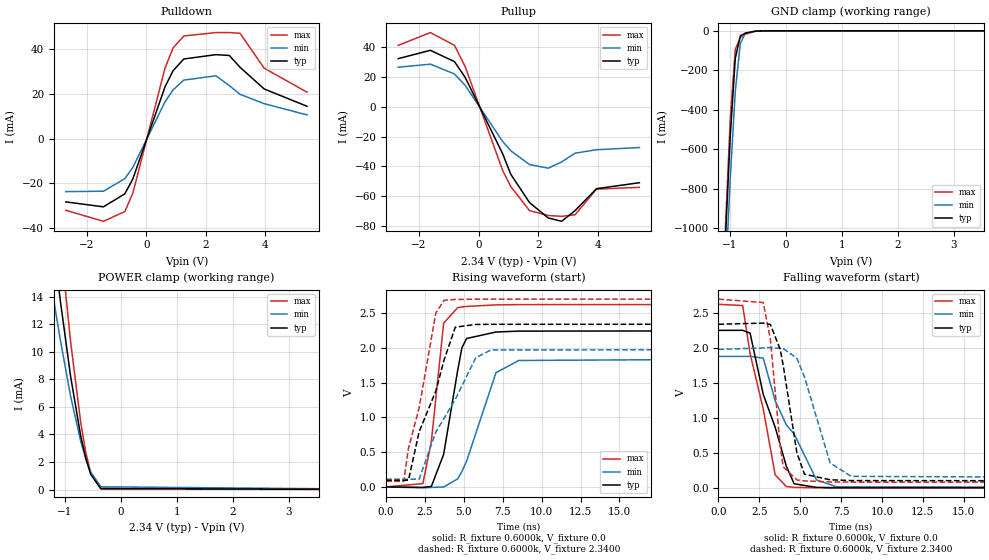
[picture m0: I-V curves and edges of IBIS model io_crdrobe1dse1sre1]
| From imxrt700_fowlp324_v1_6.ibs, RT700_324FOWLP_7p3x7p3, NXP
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[Model] io_crdrobe1dse1sre1
|   Model io_crdrobe1dse1sre1
| This model was characterised for following simulation conditions:
| External (pad) voltage:
|   - Typ: 2.34V,   - Min: 1.98V,   - Max: 2.7V
| Library cells for typ/min/max conditions are connected as defined below:
|  PAD_IO - External Pad
|  ipp_do - Core Input
|  ipp_obe - Output Buffer Enable
|  ASRCN3V3[3] - NC
|  ASRCN3V3[4] - NC
|  ASRCP3V3[4] - NC
|  REFAPBIAS3V3 - gnde
|  REFBAMPL3V3 - vdd1v8
|  REFCAMPH3V3 - vdd1v8
|  REFDNBIAS3V3 - vdd1v8
|  REFH3V3 - REFH3V3
|  REFL3V3 - REFL3V3
|  gnde - gnde
|  ipp_dse - vdd
|  ipp_ina235_3v - NC
|  ipp_ina40_3v - NC
|  ipp_ina_mux - NC
|  ipp_ind - NC
|  ipp_ind_1p8v - NC
|  ipp_ind_3v - NC
|  ipp_sre - vdd
|  vdd - vdd
|  vdd1v8 - vdd1v8
|  vdda - vdde3v3
|  vdde3v3 - vdde3v3
| All other pins connected to ground
Model_type I/O
Polarity   Non-Inverting
Enable   Active-High
Vinl =   0.7020V
Vinh =   1.6300V
Vmeas =  1.1700V
Cref =   15.0000pF
Rref =   0.6000k
Vref =   0.0V
C_comp   3.9951pF   3.8194pF   4.1033pF
|C_comp_pullup   0.5141pF   0.5881pF   0.4996pF
|C_comp_pulldown   2.0716pF   2.1607pF   1.8543pF
[Model Spec]
| variable   typ   min   max
Vinh   1.6300V   NA   NA
Vinl   0.7020V   NA   NA
Vref   0.0V   0.0V   0.0V
Cref   15.0000pF   15.0000pF   15.0000pF
Rref   0.6000k   0.6000k   0.6000k
[Receiver Thresholds]
Vcross_high  =   0.0V
Vcross_low  =   0.0V
Vdiff_ac  =   0.0V
Vdiff_dc  =   0.0V
Tdiffslew_ac  =   0.0S
[Temperature Range]   25.0000   0.1250k   -40.0000
[Voltage Range]   2.3400V   1.9800V   2.7000V
[Pullup Reference]   2.3400V   1.9800V   2.7000V
[Pulldown Reference]   0.0V   0.0V   0.0V
[POWER Clamp Reference]   2.3400V   1.9800V   2.7000V
[GND Clamp Reference]   0.0V   0.0V   0.0V
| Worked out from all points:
|   slope of the pulldown table from 0 to 0.351 V, typ, clamps not added: 25.9 ohm
|   slope of the pullup table from 0 to 0.351 V, typ, clamps not added: 23.9 ohm
|   GND clamp passes 1 mA (typ) near -0.49 V on its own axis
|   POWER clamp passes 1 mA (typ) near -0.53 V on its own axis
|   rising waveform, R_fixture 0.6000k, V_fixture 0.0: 20-80 % time 1.01ns typ, 1.62ns min, 726ps max; typ from 0 V to 2.25 V
|   rising waveform, R_fixture 0.6000k, V_fixture 2.3400: 20-80 % time 1.99ns typ, 2.68ns min, 1.48ns max; typ from 0.094 V to 2.34 V
|   falling waveform, R_fixture 0.6000k, V_fixture 0.0: 20-80 % time 1.77ns typ, 2.34ns min, 1.42ns max; typ from 2.25 V to 0 V
|   falling waveform, R_fixture 0.6000k, V_fixture 2.3400: 20-80 % time 898ps typ, 1.4ns min, 627ps max; typ from 2.34 V to 0.094 V
[Pulldown]
|Voltage   I(typ)   I(min)   I(max)
-2.7V     -28.24mA   -23.65mA   -31.99mA
-1.44V    -30.44mA   -23.46mA   -36.9mA
-720mV    -24.64mA   -17.86mA   -32.55mA
-450mV    -17.94mA   -12.78mA   -24.31mA
630mV     23.17mA    16.47mA    31.53mA
900mV     30.36mA    21.79mA    40.52mA
1.26V     35.6mA     26.18mA    45.89mA
2.34V     37.55mA    28.09mA    47.4mA
2.79V     37.18mA    23.71mA    47.41mA
3.15V     31.9mA     19.83mA    47.08mA
3.96V     22.22mA    15.65mA    31.51mA
5.4V      14.48mA    10.63mA    20.78mA
[Pullup]
|Voltage   I(typ)   I(min)   I(max)
-2.7V     32.17mA    26.42mA    41.07mA
-1.62V    37.75mA    28.48mA    49.64mA
-810mV    30.19mA    21.88mA    41.07mA
-450mV    19.57mA    14.2mA     26.75mA
810mV     -31.62mA   -23.37mA   -42.81mA
1.08V     -45.27mA   -29.51mA   -53.51mA
1.71V     -64.26mA   -38.77mA   -69.65mA
2.34V     -74.59mA   -41.23mA   -72.91mA
2.79V     -76.8mA    -37.01mA   -73.48mA
3.24V     -69.65mA   -31.16mA   -72.4mA
3.96V     -54.95mA   -28.85mA   -55.25mA
5.4V      -50.96mA   -27.4mA    -54.05mA
[GND_clamp]
|Voltage   I(typ)   I(min)   I(max)
-2.7V     -12.91A    -12.88A    -13.56A
-1.08V    -1.077A    -1.286A    -1.025A
-990mV    -533.6mA   -749.4mA   -449.1mA
-900mV    -139.2mA   -307mA     -94.25mA
-810mV    -25.49mA   -63.91mA   -32.87mA
-720mV    -11.78mA   -11.41mA   -16.65mA
-540mV    -1.684mA   -1.901mA   -2.149mA
-360mV    -36.04uA   -133.3uA   -15.05uA
5.4V      0A         0A         0A
[POWER_clamp]
|Voltage   I(typ)   I(min)   I(max)
-2.7V     73.96mA    57.58mA    95.4mA
-1.44V    26.15mA    20.18mA    34.67mA
-1.35V    22.86mA    17.7mA     30.34mA
-1.26V    19.66mA    15.3mA     26.09mA
-1.17V    16.56mA    12.98mA    21.97mA
-1.08V    13.59mA    10.78mA    17.99mA
-900mV    8.212mA    6.776mA    10.73mA
-720mV    3.9mA      3.518mA    4.888mA
-630mV    2.284mA    2.252mA    2.724mA
-540mV    1.103mA    1.268mA    1.195mA
-360mV    77.93uA    204.3uA    41.52uA
5.4V      0A         0A         0A
[Ramp]
| variable   typ   min   max
dV/dt_r  1.3518/1.0069n   1.1288/1.6186n   1.5755/0.7263n
dV/dt_f  1.3475/0.8978n   1.1218/1.3992n   1.5719/0.6275n
R_load = 0.6000k
[Rising Waveform]
R_fixture= 0.6000k
V_fixture= 0.0
V_fixture_min= 0.0
V_fixture_max= 0.0
|time   V(typ)   V(min)   V(max)
0s        54.47nV    1.425uV    18.12nV
2.36ns    -6.455mV   -13.67mV   47.62mV
2.905ns   6.495mV    -7.219mV   652.5mV
3.695ns   467.5mV    -1.992mV   2.353V
4.592ns   1.667V     115mV      2.577V
4.869ns   2.001V     220.2mV    2.587V
5.174ns   2.134V     372.9mV    2.595V
7.058ns   2.227V     1.643V     2.617V
8.526ns   2.24V      1.818V     2.621V
60ns      2.253V     1.881V     2.626V
[Rising Waveform]
R_fixture= 0.6000k
V_fixture= 2.3400
V_fixture_min= 1.9800
V_fixture_max= 2.7000
|time   V(typ)   V(min)   V(max)
0s        94.13mV    110.3mV    80.1mV
1.134ns   93.57mV    110.2mV    79.77mV
1.435ns   97.56mV    109.9mV    557mV
2.118ns   791.6mV    110mV      1.134V
3.196ns   1.38V      790.7mV    2.503V
3.725ns   1.827V     987.9mV    2.683V
4.446ns   2.297V     1.259V     2.695V
5.758ns   2.336V     1.857V     2.699V
6.733ns   2.338V     1.969V     2.699V
60ns      2.34V      1.98V      2.7V
[Falling Waveform]
R_fixture= 0.6000k
V_fixture= 0.0
V_fixture_min= 0.0
V_fixture_max= 0.0
|time   V(typ)   V(min)   V(max)
0s        2.253V     1.881V     2.626V
1.48ns    2.254V     1.881V     2.608V
1.933ns   2.213V     1.881V     1.92V
2.736ns   1.338V     1.856V     1.128V
3.47ns    865.7mV    1.245V     184.5mV
4.15ns    308.2mV    900.4mV    18.52mV
4.628ns   58.52mV    770.6mV    7.186mV
5.996ns   6.508mV    113.4mV    1.114mV
7.243ns   2.463mV    14.12mV    307.8uV
60ns      2.612uV    7.08uV     475.4nV
[Falling Waveform]
R_fixture= 0.6000k
V_fixture= 2.3400
V_fixture_min= 1.9800
V_fixture_max= 2.7000
|time   V(typ)   V(min)   V(max)
0s        2.34V      1.98V      2.7V
2.739ns   2.357V     2.002V     2.651V
3.174ns   2.337V     2.009V     2.122V
3.776ns   1.979V     1.995V     593.6mV
3.959ns   1.753V     1.992V     300.8mV
4.792ns   502.8mV    1.855V     113.5mV
5.257ns   195.7mV    1.588V     99.27mV
6.825ns   115.5mV    356.6mV    84.97mV
8.111ns   104.2mV    164.8mV    82.12mV
60ns      94.14mV    110.3mV    80.1mV
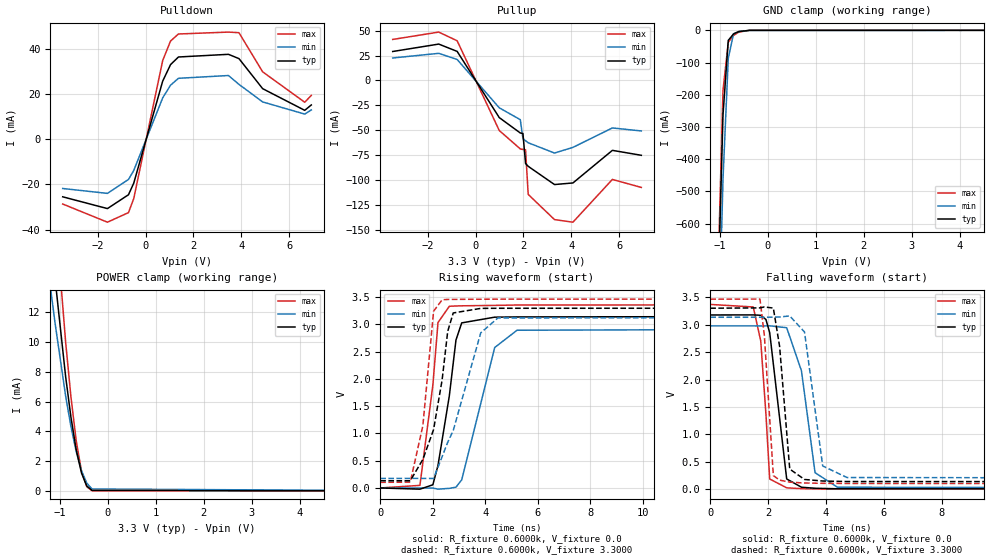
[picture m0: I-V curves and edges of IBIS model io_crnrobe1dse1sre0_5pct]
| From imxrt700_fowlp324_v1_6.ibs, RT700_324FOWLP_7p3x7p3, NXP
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[Model] io_crnrobe1dse1sre0_5pct
|   Model io_crnrobe1dse1sre0_5pct
| This model was characterised for following simulation conditions:
| External (pad) voltage:
|   - Typ: 3.3V,   - Min: 3.135V,   - Max: 3.465V
| Library cells for typ/min/max conditions are connected as defined below:
|  PAD_IO - External Pad
|  ipp_do - Core Input
|  ipp_obe - Output Buffer Enable
|  ASRCN3V3[3] - NC
|  ASRCN3V3[4] - NC
|  ASRCP3V3[4] - NC
|  REFAPBIAS3V3 - gnde
|  REFBAMPL3V3 - vdd1v8
|  REFCAMPH3V3 - vdd1v8
|  REFDNBIAS3V3 - vdd1v8
|  REFH3V3 - REFH3V3
|  REFL3V3 - REFL3V3
|  gnde - gnde
|  ipp_dse - vdd
|  ipp_ina235_3v - NC
|  ipp_ina40_3v - NC
|  ipp_ina_mux - NC
|  ipp_ind - NC
|  ipp_ind_1p8v - NC
|  ipp_ind_3v - NC
|  ipp_sre - gnde
|  vdd - vdd
|  vdd1v8 - vdd1v8
|  vdda - vdde3v3
|  vdde3v3 - vdde3v3
| All other pins connected to ground
Model_type I/O
Polarity   Non-Inverting
Enable   Active-High
Vinl =   0.9900V
Vinh =   2.3100V
Vmeas =  1.6500V
Cref =   15.0000pF
Rref =   0.6000k
Vref =   0.0V
C_comp   4.0038pF   3.8208pF   4.1241pF
|C_comp_pullup   0.5150pF   0.5903pF   0.4959pF
|C_comp_pulldown   2.0815pF   2.1810pF   1.8613pF
[Model Spec]
| variable   typ   min   max
Vinh   2.3100V   NA   NA
Vinl   0.9900V   NA   NA
Vref   0.0V   0.0V   0.0V
Cref   15.0000pF   15.0000pF   15.0000pF
Rref   0.6000k   0.6000k   0.6000k
[Receiver Thresholds]
Vcross_high  =   0.0V
Vcross_low  =   0.0V
Vdiff_ac  =   0.0V
Vdiff_dc  =   0.0V
Tdiffslew_ac  =   0.0S
[Temperature Range]   25.0000   0.1250k   -40.0000
[Voltage Range]   3.3000V   3.1350V   3.4650V
[Pullup Reference]   3.3000V   3.1350V   3.4650V
[Pulldown Reference]   0.0V   0.0V   0.0V
[POWER Clamp Reference]   3.3000V   3.1350V   3.4650V
[GND Clamp Reference]   0.0V   0.0V   0.0V
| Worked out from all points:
|   slope of the pulldown table from 0 to 0.495 V, typ, clamps not added: 26.4 ohm
|   slope of the pullup table from 0 to 0.495 V, typ, clamps not added: 24.4 ohm
|   GND clamp passes 1 mA (typ) near -0.50 V on its own axis
|   POWER clamp passes 1 mA (typ) near -0.52 V on its own axis
|   rising waveform, R_fixture 0.6000k, V_fixture 0.0: 20-80 % time 549ps typ, 813ps min, 418ps max; typ from 0 V to 3.18 V
|   rising waveform, R_fixture 0.6000k, V_fixture 3.3000: 20-80 % time 718ps typ, 1.14ns min, 459ps max; typ from 0.133 V to 3.3 V
|   falling waveform, R_fixture 0.6000k, V_fixture 0.0: 20-80 % time 329ps typ, 474ps min, 238ps max; typ from 3.18 V to 0 V
|   falling waveform, R_fixture 0.6000k, V_fixture 3.3000: 20-80 % time 280ps typ, 398ps min, 209ps max; typ from 3.3 V to 0.133 V
[Pulldown]
|Voltage   I(typ)   I(min)   I(max)
-3.465V   -25.47mA   -21.79mA   -28.66mA
-1.595V   -30.68mA   -23.95mA   -36.7mA
-715mV    -24.55mA   -17.79mA   -32.46mA
-495mV    -19.43mA   -13.83mA   -26.26mA
715mV     25.71mA    18.31mA    34.82mA
1.045V    33.06mA    23.94mA    43.49mA
1.375V    36.41mA    26.98mA    46.59mA
3.465V    37.59mA    28.21mA    47.43mA
3.905V    35.69mA    24.29mA    47.16mA
4.895V    22.39mA    16.52mA    29.84mA
6.655V    12.8mA     11.14mA    16.38mA
6.93V     15.19mA    12.98mA    19.44mA
[Pullup]
|Voltage   I(typ)   I(min)   I(max)
-3.465V   29.1mA     22.59mA    41.21mA
-1.54V    36.55mA    27.24mA    48.59mA
-770mV    29.19mA    21.06mA    39.85mA
990mV     -37.26mA   -27.44mA   -50.23mA
1.87V     -52.73mA   -39.38mA   -68.73mA
1.98V     -53.28mA   -58.42mA   -69.28mA
2.09V     -83.35mA   -60.56mA   -69.66mA
2.2V      -86.2mA    -62.53mA   -114.4mA
3.3V      -104.5mA   -72.86mA   -139.7mA
4.07V     -102.9mA   -67.18mA   -142.3mA
5.72V     -70.17mA   -47.67mA   -99.37mA
6.93V     -75.13mA   -50.69mA   -107.4mA
[GND_clamp]
|Voltage   I(typ)   I(min)   I(max)
-3.465V   -18.65A    -18.54A    -19.59A
-1.045V   -856.3mA   -1.07A     -789.2mA
-935mV    -262.9mA   -462.2mA   -186.4mA
-825mV    -31.14mA   -87.01mA   -37.16mA
-715mV    -11.21mA   -10.51mA   -15.88mA
-605mV    -3.859mA   -3.519mA   -5.394mA
-385mV    -79.67uA   -219.6uA   -43.93uA
6.93V     0A         0A         0A
[POWER_clamp]
|Voltage   I(typ)   I(min)   I(max)
-3.465V   98.91mA    78.43mA    126mA
-1.43V    25.78mA    19.9mA     34.19mA
-1.32V    21.78mA    16.89mA    28.92mA
-1.21V    17.92mA    14mA       23.79mA
-1.1V     14.24mA    11.26mA    18.86mA
-880mV    7.673mA    6.373mA    9.998mA
-770mV    4.965mA    4.333mA    6.33mA
-660mV    2.777mA    2.644mA    3.379mA
-550mV    1.212mA    1.363mA    1.332mA
-440mV    333.5uA    531.5uA    282.6uA
-330mV    37.61uA    130.9uA    15.04uA
6.93V     0A         0A         0A
[Ramp]
| variable   typ   min   max
dV/dt_r  1.9062/0.5490n   1.7865/0.8131n   2.0217/0.4182n
dV/dt_f  1.9001/0.2799n   1.7755/0.3982n   2.0172/0.2091n
R_load = 0.6000k
[Rising Waveform]
R_fixture= 0.6000k
V_fixture= 0.0
V_fixture_min= 0.0
V_fixture_max= 0.0
|time   V(typ)   V(min)   V(max)
0s        57.42nV    1.437uV    26.77nV
1.51ns    -22.02mV   -541.7uV   47.52mV
2.002ns   58.42mV    -1.774mV   1.884V
2.198ns   414mV      -21.5mV    3.034V
2.63ns    1.691V     -7.389mV   3.333V
2.882ns   2.712V     14.49mV    3.338V
3.101ns   3.028V     148.3mV    3.341V
4.357ns   3.133V     2.576V     3.349V
5.207ns   3.137V     2.893V     3.356V
60ns      3.177V     2.978V     3.369V
[Rising Waveform]
R_fixture= 0.6000k
V_fixture= 3.3000
V_fixture_min= 3.1350
V_fixture_max= 3.4650
|time   V(typ)   V(min)   V(max)
0s        133.2mV    175.8mV    103mV
1.142ns   132.4mV    175.8mV    107.2mV
1.622ns   523.3mV    175.6mV    1.143V
2.03ns    1.071V     174.4mV    3.242V
2.355ns   1.982V     574.3mV    3.452V
2.568ns   2.873V     837.9mV    3.458V
2.778ns   3.21V      1.053V     3.459V
3.826ns   3.294V     2.845V     3.462V
4.479ns   3.296V     3.119V     3.463V
60ns      3.3V       3.135V     3.465V
[Falling Waveform]
R_fixture= 0.6000k
V_fixture= 0.0
V_fixture_min= 0.0
V_fixture_max= 0.0
|time   V(typ)   V(min)   V(max)
0s        3.177V     2.978V     3.369V
1.485ns   3.178V     2.978V     3.323V
1.744ns   3.171V     2.977V     2.7V
1.923ns   3.094V     2.978V     1.366V
2.053ns   2.854V     2.979V     185.4mV
2.64ns    186.1mV    2.944V     24.21mV
3.15ns    35.73mV    2.159V     9.592mV
3.62ns    16.72mV    300.3mV    4.641mV
4.397ns   7.244mV    34.55mV    1.722mV
60ns      1.139uV    1.872uV    979nV
[Falling Waveform]
R_fixture= 0.6000k
V_fixture= 3.3000
V_fixture_min= 3.1350
V_fixture_max= 3.4650
|time   V(typ)   V(min)   V(max)
0s        3.3V       3.135V     3.465V
1.717ns   3.306V     3.135V     3.467V
1.868ns   3.323V     3.134V     2.804V
2.179ns   3.303V     3.138V     247.4mV
2.395ns   2.605V     3.14V      165.1mV
2.745ns   366.4mV    3.159V     128mV
3.256ns   176.7mV    2.866V     112.4mV
3.884ns   148.6mV    423.4mV    106.5mV
4.724ns   139.3mV    212.2mV    104.2mV
60ns      133.2mV    175.8mV    103mV
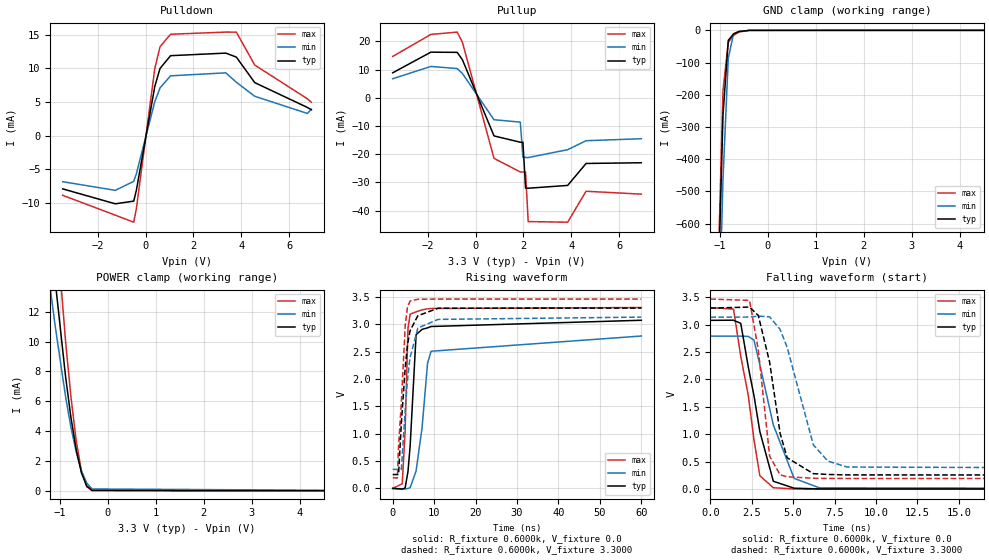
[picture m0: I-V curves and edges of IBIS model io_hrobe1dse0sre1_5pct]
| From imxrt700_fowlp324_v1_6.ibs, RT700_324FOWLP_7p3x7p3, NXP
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[Model] io_hrobe1dse0sre1_5pct
|   Model io_hrobe1dse0sre1_5pct
| This model was characterised for following simulation conditions:
| External (pad) voltage:
|   - Typ: 3.3V,   - Min: 3.135V,   - Max: 3.465V
| Library cells for typ/min/max conditions are connected as defined below:
|  PAD_IO - External Pad
|  ipp_do - Core Input
|  ipp_obe - Output Buffer Enable
|  ASRCN3V3[3] - NC
|  ASRCN3V3[4] - NC
|  ASRCP3V3[4] - NC
|  REFAPBIAS3V3 - gnde
|  REFBAMPL3V3 - vdd1v8
|  REFCAMPH3V3 - vdd1v8
|  REFDNBIAS3V3 - vdd1v8
|  REFH3V3 - REFH3V3
|  REFL3V3 - REFL3V3
|  gnde - gnde
|  ipp_dse - gnde
|  ipp_ina235_3v - NC
|  ipp_ina40_3v - NC
|  ipp_ina_mux - NC
|  ipp_ind - NC
|  ipp_ind_1p8v - NC
|  ipp_ind_3v - NC
|  ipp_sre - vdd
|  vdd - vdd
|  vdd1v8 - vdd1v8
|  vdda - vdde3v3
|  vdde3v3 - vdde3v3
| All other pins connected to ground
Model_type I/O
Polarity   Non-Inverting
Enable   Active-High
Vinl =   0.9900V
Vinh =   2.3100V
Vmeas =  1.6500V
Cref =   15.0000pF
Rref =   0.6000k
Vref =   0.0V
C_comp   4.0008pF   3.8187pF   4.1208pF
|C_comp_pullup   0.5641pF   0.7322pF   0.4697pF
|C_comp_pulldown   2.1155pF   2.2154pF   1.8987pF
[Model Spec]
| variable   typ   min   max
Vinh   2.3100V   NA   NA
Vinl   0.9900V   NA   NA
Vref   0.0V   0.0V   0.0V
Cref   15.0000pF   15.0000pF   15.0000pF
Rref   0.6000k   0.6000k   0.6000k
[Receiver Thresholds]
Vcross_high  =   0.0V
Vcross_low  =   0.0V
Vdiff_ac  =   0.0V
Vdiff_dc  =   0.0V
Tdiffslew_ac  =   0.0S
[Temperature Range]   25.0000   0.1250k   -40.0000
[Voltage Range]   3.3000V   3.1350V   3.4650V
[Pullup Reference]   3.3000V   3.1350V   3.4650V
[Pulldown Reference]   0.0V   0.0V   0.0V
[POWER Clamp Reference]   3.3000V   3.1350V   3.4650V
[GND Clamp Reference]   0.0V   0.0V   0.0V
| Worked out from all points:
|   slope of the pulldown table from 0 to 0.495 V, typ, clamps not added: 56 ohm
|   slope of the pullup table from 0 to 0.495 V, typ, clamps not added: 48.9 ohm
|   GND clamp passes 1 mA (typ) near -0.50 V on its own axis
|   POWER clamp passes 1 mA (typ) near -0.52 V on its own axis
|   rising waveform, R_fixture 0.6000k, V_fixture 0.0: 20-80 % time 1.2ns typ, 2.14ns min, 769ps max; typ from 0 V to 3.08 V
|   rising waveform, R_fixture 0.6000k, V_fixture 3.3000: 20-80 % time 1.91ns typ, 2.06ns min, 1.39ns max; typ from 0.254 V to 3.3 V
|   falling waveform, R_fixture 0.6000k, V_fixture 0.0: 20-80 % time 1.13ns typ, 1.51ns min, 1.02ns max; typ from 3.08 V to 0 V
|   falling waveform, R_fixture 0.6000k, V_fixture 3.3000: 20-80 % time 973ps typ, 1.45ns min, 687ps max; typ from 3.3 V to 0.254 V
[Pulldown]
|Voltage   I(typ)   I(min)   I(max)
-3.465V   -7.89mA    -6.82mA    -8.84mA
-1.265V   -10.1mA    -8.106mA   -11.79mA
-495mV    -9.702mA   -6.762mA   -12.83mA
-385mV    -8.098mA   -5.646mA   -10.83mA
385mV     7.309mA    5.061mA    9.964mA
605mV     9.989mA    7.101mA    13.21mA
1.045V    11.88mA    8.892mA    15.06mA
3.355V    12.26mA    9.333mA    15.38mA
3.795V    11.67mA    7.934mA    15.37mA
4.565V    7.878mA    5.856mA    10.49mA
6.765V    4.198mA    3.305mA    5.483mA
6.93V     3.854mA    3.926mA    4.97mA
[Pullup]
|Voltage   I(typ)   I(min)   I(max)
-3.465V   8.87mA     6.768mA    14.67mA
-1.87V    16.19mA    11.13mA    22.48mA
-770mV    16.12mA    10.37mA    23.31mA
-550mV    13.49mA    8.623mA    19.7mA
770mV     -13.51mA   -7.773mA   -21.46mA
1.87V     -15.75mA   -8.627mA   -26.3mA
1.98V     -15.77mA   -21.1mA    -26.32mA
2.09V     -32mA      -21.15mA   -26.35mA
2.2V      -32.06mA   -21.19mA   -43.89mA
3.85V     -31.07mA   -18.4mA    -44.11mA
4.62V     -23.28mA   -15.21mA   -33.14mA
6.93V     -23.03mA   -14.51mA   -34.16mA
[GND_clamp]
|Voltage   I(typ)   I(min)   I(max)
-3.465V   -18.65A    -18.54A    -19.59A
-1.045V   -856.4mA   -1.07A     -789.2mA
-935mV    -262.9mA   -462.2mA   -186.4mA
-825mV    -31.14mA   -87.01mA   -37.16mA
-715mV    -11.21mA   -10.51mA   -15.88mA
-605mV    -3.859mA   -3.519mA   -5.394mA
-385mV    -79.74uA   -219.6uA   -43.96uA
6.93V     0A         0A         0A
[POWER_clamp]
|Voltage   I(typ)   I(min)   I(max)
-3.465V   98.76mA    78.08mA    125.9mA
-1.43V    25.63mA    19.65mA    34.12mA
-1.32V    21.65mA    16.67mA    28.86mA
-1.21V    17.8mA     13.81mA    23.74mA
-1.1V     14.15mA    11.1mA     18.82mA
-880mV    7.624mA    6.286mA    9.977mA
-770mV    4.936mA    4.278mA    6.317mA
-660mV    2.762mA    2.615mA    3.373mA
-550mV    1.207mA    1.351mA    1.33mA
-440mV    332.8uA    528.9uA    282.4uA
-330mV    37.59uA    131uA      15.04uA
6.93V     0A         0A         0A
[Ramp]
| variable   typ   min   max
dV/dt_r  1.8464/1.2036n   1.6736/2.1423n   1.9857/0.7688n
dV/dt_f  1.8274/0.9727n   1.6719/1.4474n   1.9622/0.6874n
R_load = 0.6000k
[Rising Waveform]
R_fixture= 0.6000k
V_fixture= 0.0
V_fixture_min= 0.0
V_fixture_max= 0.0
|time   V(typ)   V(min)   V(max)
0s        180nV      2.99uV     125.3nV
2.296ns   -10.97mV   -13.62mV   85.45mV
2.993ns   7.573mV    -7.961mV   1.044V
3.688ns   309.5mV    -2.119mV   2.929V
4.214ns   783.9mV    15.05mV    3.189V
5.643ns   2.813V     319.3mV    3.231V
7.091ns   2.911V     1.115V     3.268V
8.405ns   2.938V     2.288V     3.286V
9.259ns   2.963V     2.51V      3.293V
60ns      3.077V     2.789V     3.31V
[Rising Waveform]
R_fixture= 0.6000k
V_fixture= 3.3000
V_fixture_min= 3.1350
V_fixture_max= 3.4650
|time   V(typ)   V(min)   V(max)
0s        254.3mV    348.5mV    194.7mV
1.117ns   253.9mV    348.4mV    191.3mV
1.409ns   254.2mV    348mV      766.8mV
2.092ns   1.203V     348.4mV    1.585V
3.032ns   2.225V     1.452V     2.993V
3.561ns   2.624V     1.98V      3.315V
4.179ns   2.883V     2.393V     3.429V
6.069ns   3.16V      2.934V     3.462V
10.95ns   3.297V     3.093V     3.465V
60ns      3.3V       3.135V     3.465V
[Falling Waveform]
R_fixture= 0.6000k
V_fixture= 0.0
V_fixture_min= 0.0
V_fixture_max= 0.0
|time   V(typ)   V(min)   V(max)
0s        3.077V     2.79V      3.31V
1.401ns   3.08V      2.79V      3.282V
1.839ns   3.023V     2.789V     2.419V
2.293ns   2.226V     2.784V     1.708V
2.636ns   1.706V     2.716V     902.4mV
2.991ns   1.05V      2.267V     243.5mV
3.804ns   144.3mV    1.171V     26.13mV
5.057ns   17.5mV     197.3mV    4.029mV
6.583ns   5.023mV    24.07mV    697.5uV
60ns      675.2nV    2.199uV    396nV
[Falling Waveform]
R_fixture= 0.6000k
V_fixture= 3.3000
V_fixture_min= 3.1350
V_fixture_max= 3.4650
|time   V(typ)   V(min)   V(max)
0s        3.3V       3.135V     3.465V
2.368ns   3.319V     3.137V     3.441V
2.897ns   3.166V     3.154V     2.54V
3.581ns   2.313V     3.141V     602.4mV
4.215ns   1.014V     2.91V      260.6mV
4.637ns   572.4mV    2.585V     226mV
6.217ns   282.9mV    807.2mV    198.7mV
7.092ns   267.9mV    512.4mV    196.3mV
8.249ns   260mV      403.6mV    195.1mV
60ns      254.3mV    348.5mV    194.7mV
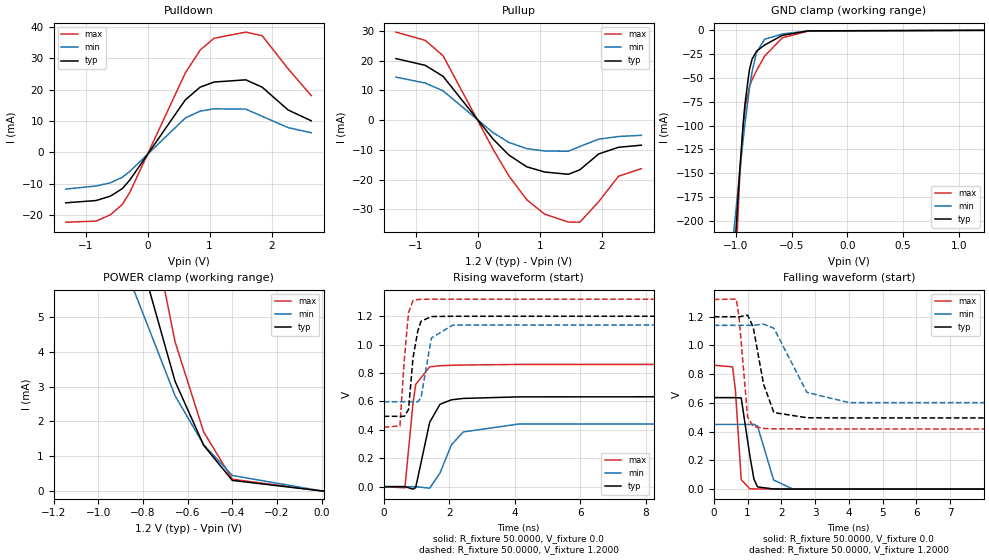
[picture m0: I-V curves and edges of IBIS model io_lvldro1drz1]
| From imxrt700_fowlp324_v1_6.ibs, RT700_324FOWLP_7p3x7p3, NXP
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[Model] io_lvldro1drz1
|   Model io_lvldro1drz1
| This model was characterised for following simulation conditions:
| External (pad) voltage:
|   - Typ: 1.2V,   - Min: 1.14V,   - Max: 1.32V
| Library cells for typ/min/max conditions are connected as defined below:
|  ipp_io - External Pad
|  ipp_do - Core Input
|  ipp_obe - Output Buffer Enable
|  config1v21v8 - vdd
|  drive0 - vdd
|  drive1 - vdd
|  gnd - gnd
|  gnde - gnde
|  ncgather - NC
|  vdd - vdd
|  vdde1v8 - vdde1v8
| All other pins connected to ground
Model_type I/O
Polarity   Non-Inverting
Enable   Active-Low
Vinl =   0.3600V
Vinh =   0.8400V
Vmeas =  0.6000V
Cref =   30.0000pF
Rref =   1.0000M
Vref =   1.2000V
C_comp   2.6178pF   2.5672pF   2.7119pF
|C_comp_pullup   1.3434pF   1.4016pF   1.2843pF
|C_comp_pulldown   0.0F   0.0F   0.0F
[Model Spec]
| variable   typ   min   max
Vinh   0.8400V   NA   NA
Vinl   0.3600V   NA   NA
Vref   1.8000V   1.8000V   1.8000V
Cref   30.0000pF   30.0000pF   30.0000pF
Rref   1.0000M   1.0000M   1.0000M
[Temperature Range]   25.0000   0.1250k   -40.0000
[Voltage Range]   1.2000V   1.1400V   1.3200V
[Pullup Reference]   1.2000V   1.1400V   1.3200V
[Pulldown Reference]   0.0V   0.0V   0.0V
[POWER Clamp Reference]   1.2000V   1.1400V   1.3200V
[GND Clamp Reference]   0.0V   0.0V   0.0V
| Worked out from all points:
|   slope of the pulldown table from 0 to 0.18 V, typ, clamps not added: 33.6 ohm
|   slope of the pullup table from 0 to 0.18 V, typ, clamps not added: 38.8 ohm
|   GND clamp passes 1 mA (typ) near -0.39 V on its own axis
|   POWER clamp passes 1 mA (typ) near -0.49 V on its own axis
|   rising waveform, R_fixture 50.0000, V_fixture 0.0: 20-80 % time 367ps typ, 579ps min, 209ps max; typ from 0 V to 0.637 V
|   rising waveform, R_fixture 50.0000, V_fixture 1.2000: 20-80 % time 209ps typ, 237ps min, 162ps max; typ from 0.495 V to 1.2 V
|   falling waveform, R_fixture 50.0000, V_fixture 0.0: 20-80 % time 226ps typ, 327ps min, 133ps max; typ from 0.637 V to 0 V
|   falling waveform, R_fixture 50.0000, V_fixture 1.2000: 20-80 % time 332ps typ, 647ps min, 176ps max; typ from 1.2 V to 0.495 V
[Pulldown]
|Voltage   I(typ)   I(min)   I(max)
-1.32V    -16.03mA   -11.66mA   -22.2mA
-832mV    -15.31mA   -10.68mA   -21.86mA
-600mV    -13.9mA    -9.665mA   -19.84mA
-408mV    -11.51mA   -7.885mA   -16.54mA
-288mV    -8.796mA   -6.028mA   -12.75mA
608mV     16.73mA    10.98mA    25.31mA
848mV     20.79mA    13.15mA    32.6mA
1.072V    22.42mA    13.9mA     36.34mA
1.584V    23.12mA    13.79mA    38.32mA
1.848V    20.79mA    11.52mA    37.17mA
2.264V    13.56mA    7.926mA    26.71mA
2.64V     10.08mA    6.282mA    18.11mA
[Pullup]
|Voltage   I(typ)   I(min)   I(max)
-1.32V    20.72mA    14.48mA    29.63mA
-848mV    18.46mA    12.51mA    26.85mA
-560mV    14.77mA    9.89mA     21.71mA
248mV     -6.352mA   -4.196mA   -9.772mA
504mV     -11.74mA   -7.481mA   -18.78mA
792mV     -15.67mA   -9.557mA   -26.76mA
1.08V     -17.42mA   -10.37mA   -31.58mA
1.464V    -18.18mA   -10.42mA   -34.23mA
1.648V    -16.66mA   -8.821mA   -34.29mA
1.952V    -11.34mA   -6.377mA   -27.39mA
2.272V    -9.102mA   -5.473mA   -18.82mA
2.64V     -8.393mA   -5.086mA   -16.3mA
[GND_clamp]
|Voltage   I(typ)   I(min)   I(max)
-1.32V    -824mA     -526.2mA   -1.227A
-1.032V   -269.6mA   -225.5mA   -323.8mA
-968mV    -148.5mA   -150.4mA   -156.4mA
-936mV    -98.26mA   -114.7mA   -100.6mA
-920mV    -77.35mA   -98.01mA   -82.61mA
-880mV    -41.26mA   -61.23mA   -59.25mA
-856mV    -30.33mA   -43.55mA   -51.86mA
-816mV    -21.94mA   -23.19mA   -42.16mA
-744mV    -15.43mA   -9.413mA   -27.16mA
-584mV    -5.259mA   -3.813mA   -7.801mA
-352mV    -567.9uA   -545.2uA   -812.4uA
1.224V    19.17nA    663.1nA    12.5nA
[POWER_clamp]
|Voltage   I(typ)   I(min)   I(max)
-1.32V    20.26mA    15.09mA    28.18mA
-1.016V   11.36mA    8.666mA    15.85mA
-656mV    3.149mA    2.734mA    4.283mA
-528mV    1.31mA     1.329mA    1.694mA
-400mV    302.8uA    443.9uA    336uA
0V        17.28nA    129.7nA    13.53nA
8mV       16.9nA     117.4nA    13.43nA
[Ramp]
| variable   typ   min   max
dV/dt_r  0.3823/0.3669n   0.2703/0.5788n   0.5175/0.2085n
dV/dt_f  0.4229/0.3318n   0.3254/0.6461n   0.5410/0.1755n
R_load = 50.0000
[Rising Waveform]
R_fixture= 50.0000
V_fixture= 0.0
V_fixture_min= 0.0
V_fixture_max= 0.0
|time   V(typ)   V(min)   V(max)
0s        14.29nV    924.5nV    1.423nV
649.1ps   162.7uV    583.3nV    -7.856mV
893.4ps   -17.58mV   4.687uV    580mV
978.4ps   -6.39mV    -16.57uV   719.5mV
1.405ns   452.6mV    -11.01mV   842.9mV
1.72ns    579.5mV    96.26mV    850.7mV
2.071ns   611.2mV    294.9mV    853.9mV
2.429ns   620.9mV    385mV      855.9mV
4.122ns   631.9mV    440.8mV    860.1mV
60ns      637.2mV    450.5mV    862.5mV
[Rising Waveform]
R_fixture= 50.0000
V_fixture= 1.2000
V_fixture_min= 1.1400
V_fixture_max= 1.3200
|time   V(typ)   V(min)   V(max)
0s        495.1mV    597.7mV    418.4mV
496.6ps   495.1mV    597.7mV    427.3mV
636.1ps   495.3mV    597.7mV    911.3mV
761.1ps   544.3mV    597.7mV    1.226V
897.1ps   907.8mV    597.7mV    1.309V
1.044ns   1.097V     596.4mV    1.317V
1.143ns   1.164V     629.3mV    1.318V
1.458ns   1.197V     1.046V     1.319V
2.11ns    1.199V     1.137V     1.319V
60ns      1.2V       1.14V      1.32V
[Falling Waveform]
R_fixture= 50.0000
V_fixture= 0.0
V_fixture_min= 0.0
V_fixture_max= 0.0
|time   V(typ)   V(min)   V(max)
0s        637.2mV    450.5mV    862.5mV
557.9ps   637.1mV    450.5mV    851.2mV
641.1ps   637.1mV    450.4mV    687mV
812.4ps   635mV      450.4mV    66.16mV
1.066ns   236mV      450.4mV    2.872mV
1.19ns    69.02mV    451.1mV    1.793mV
1.297ns   15.59mV    438.3mV    1.433mV
1.772ns   1.477mV    63.76mV    982uV
2.326ns   815.2uV    2.51mV     776.9uV
60ns      262.9nV    3.627uV    17.05nV
[Falling Waveform]
R_fixture= 50.0000
V_fixture= 1.2000
V_fixture_min= 1.1400
V_fixture_max= 1.3200
|time   V(typ)   V(min)   V(max)
0s        1.2V       1.14V      1.32V
666.9ps   1.2V       1.14V      1.323V
748.1ps   1.199V     1.14V      1.199V
1.002ns   1.211V     1.14V      501.4mV
1.167ns   1.129V     1.14V      437.3mV
1.473ns   731.8mV    1.149V     422.7mV
1.78ns    533.1mV    1.12V      420.2mV
2.759ns   497.1mV    673.4mV    419.1mV
3.998ns   495.7mV    602.4mV    418.8mV
60ns      495.1mV    597.7mV    418.4mV
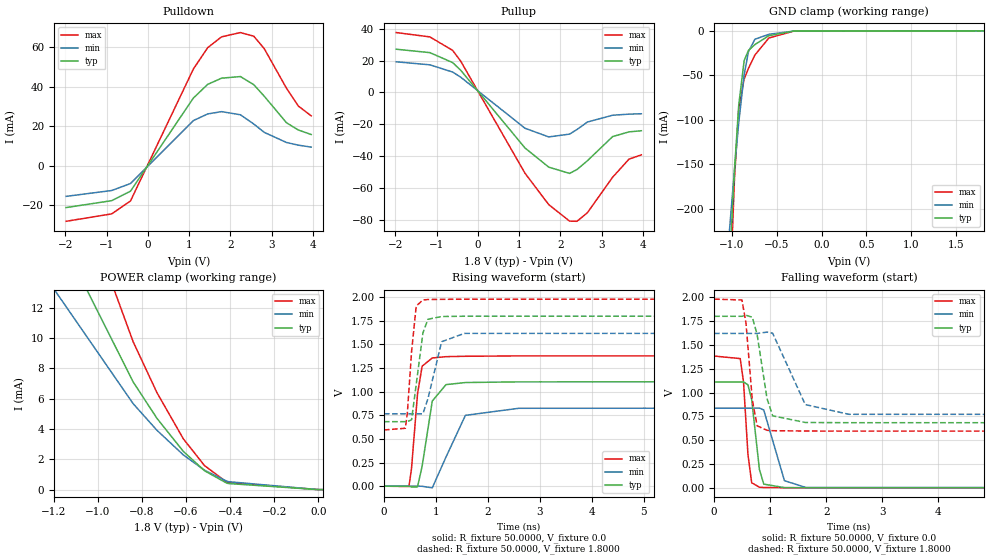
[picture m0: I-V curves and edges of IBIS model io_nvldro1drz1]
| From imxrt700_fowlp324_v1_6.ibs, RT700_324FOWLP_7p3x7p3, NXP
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[Model] io_nvldro1drz1
|   Model io_nvldro1drz1
| This model was characterised for following simulation conditions:
| External (pad) voltage:
|   - Typ: 1.8V,   - Min: 1.62V,   - Max: 1.98V
| Library cells for typ/min/max conditions are connected as defined below:
|  ipp_io - External Pad
|  ipp_do - Core Input
|  ipp_obe - Output Buffer Enable
|  config1v21v8 - gnde
|  drive0 - vdd
|  drive1 - vdd
|  gnd - gnd
|  gnde - gnde
|  ncgather - NC
|  vdd - vdd
|  vdde1v8 - vdde1v8
| All other pins connected to ground
Model_type I/O
Polarity   Non-Inverting
Enable   Active-Low
Vinl =   0.5400V
Vinh =   1.2600V
Vmeas =  0.9000V
Cref =   30.0000pF
Rref =   1.0000M
Vref =   1.8000V
C_comp   2.6161pF   2.5670pF   2.7113pF
|C_comp_pullup   1.3361pF   1.3948pF   1.2802pF
|C_comp_pulldown   0.0F   0.0F   0.0F
[Model Spec]
| variable   typ   min   max
Vinh   1.2600V   NA   NA
Vinl   0.5400V   NA   NA
Vref   1.8000V   1.8000V   1.8000V
Cref   30.0000pF   30.0000pF   30.0000pF
Rref   1.0000M   1.0000M   1.0000M
[Temperature Range]   25.0000   0.1250k   -40.0000
[Voltage Range]   1.8000V   1.6200V   1.9800V
[Pullup Reference]   1.8000V   1.6200V   1.9800V
[Pulldown Reference]   0.0V   0.0V   0.0V
[POWER Clamp Reference]   1.8000V   1.6200V   1.9800V
[GND Clamp Reference]   0.0V   0.0V   0.0V
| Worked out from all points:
|   slope of the pulldown table from 0 to 0.27 V, typ, clamps not added: 30.7 ohm
|   slope of the pullup table from 0 to 0.27 V, typ, clamps not added: 30.2 ohm
|   GND clamp passes 1 mA (typ) near -0.39 V on its own axis
|   POWER clamp passes 1 mA (typ) near -0.49 V on its own axis
|   rising waveform, R_fixture 50.0000, V_fixture 0.0: 20-80 % time 186ps typ, 312ps min, 127ps max; typ from 0 V to 1.11 V
|   rising waveform, R_fixture 50.0000, V_fixture 1.8000: 20-80 % time 148ps typ, 201ps min, 104ps max; typ from 0.682 V to 1.8 V
|   falling waveform, R_fixture 50.0000, V_fixture 0.0: 20-80 % time 122ps typ, 208ps min, 87ps max; typ from 1.11 V to 0 V
|   falling waveform, R_fixture 50.0000, V_fixture 1.8000: 20-80 % time 177ps typ, 331ps min, 116ps max; typ from 1.8 V to 0.682 V
[Pulldown]
|Voltage   I(typ)   I(min)   I(max)
-1.98V    -21.2mA    -15.52mA   -28.15mA
-876mV    -17.7mA    -12.56mA   -24.4mA
-420mV    -12.9mA    -9.028mA   -17.87mA
1.104V    34.28mA    22.86mA    48.98mA
1.452V    41.24mA    26.25mA    59.83mA
1.788V    44.36mA    27.41mA    65.3mA
2.244V    45.18mA    25.82mA    67.46mA
2.568V    41.06mA    21.13mA    65.61mA
2.82V     35.25mA    16.92mA    59.36mA
3.36V     21.78mA    11.78mA    39.25mA
3.648V    18.09mA    10.42mA    30.23mA
3.96V     15.81mA    9.423mA    25.24mA
[Pullup]
|Voltage   I(typ)   I(min)   I(max)
-1.98V    27.12mA    19.23mA    37.58mA
-1.164V   24.98mA    17.31mA    34.86mA
-612mV    18.71mA    12.77mA    26.37mA
-420mV    13.98mA    9.609mA    19.73mA
1.14V     -34.91mA   -22.51mA   -50.76mA
1.716V    -46.95mA   -27.97mA   -70.5mA
2.22V     -50.89mA   -26.21mA   -80.84mA
2.4V      -48.44mA   -23.33mA   -80.97mA
2.652V    -42.95mA   -18.62mA   -75.59mA
3.264V    -27.75mA   -14.34mA   -53.28mA
3.66V     -24.8mA    -13.66mA   -41.93mA
3.96V     -24.09mA   -13.42mA   -39.24mA
[GND_clamp]
|Voltage   I(typ)   I(min)   I(max)
-1.98V    -2.304A    -1.314A    -3.648A
-1.188V   -579.3mA   -402.9mA   -809.8mA
-1.068V   -345.9mA   -273.9mA   -436.6mA
-1.02V    -246.9mA   -214.1mA   -290.1mA
-972mV    -156.3mA   -155.7mA   -166mA
-924mV    -82.86mA   -102.6mA   -86.85mA
-864mV    -33.43mA   -49.36mA   -54.12mA
-816mV    -21.98mA   -23.37mA   -42.16mA
-744mV    -15.43mA   -9.445mA   -27.16mA
-588mV    -5.426mA   -3.899mA   -8.058mA
-312mV    -266.2uA   -304.2uA   -358.5uA
1.812V    32.97nA    20uA       18.44nA
[POWER_clamp]
|Voltage   I(typ)   I(min)   I(max)
-1.98V    43.31mA    32.26mA    59.03mA
-1.38V    22.69mA    17.01mA    31.2mA
-840mV    7.098mA    5.665mA    9.745mA
-732mV    4.698mA    3.911mA    6.391mA
-612mV    2.517mA    2.283mA    3.343mA
-516mV    1.244mA    1.28mA     1.582mA
-420mV    463.6uA    587.6uA    544.1uA
-408mV    400.2uA    523.6uA    465.2uA
0V        28.12nA    179.8nA    22.83nA
24mV      22.85nA    114.3nA    21.08nA
[Ramp]
| variable   typ   min   max
dV/dt_r  0.6660/0.1857n   0.5014/0.3116n   0.8298/0.1273n
dV/dt_f  0.6705/0.1768n   0.5126/0.3305n   0.8311/0.1164n
R_load = 50.0000
[Rising Waveform]
R_fixture= 50.0000
V_fixture= 0.0
V_fixture_min= 0.0
V_fixture_max= 0.0
|time   V(typ)   V(min)   V(max)
0s        160.7nV    1.883uV    229.1nV
480.8ps   -947.3uV   2.611uV    -4.292mV
529.5ps   -8.339mV   3.421uV    181.8mV
645.8ps   -7.992mV   -9.842uV   975.4mV
734.8ps   210.5mV    -1.518mV   1.27V
930.1ps   901.5mV    -18.08mV   1.357V
1.195ns   1.075V     309.4mV    1.371V
1.568ns   1.097V     749.6mV    1.375V
2.595ns   1.104V     824.4mV    1.379V
60ns      1.11V      835.6mV    1.383V
[Rising Waveform]
R_fixture= 50.0000
V_fixture= 1.8000
V_fixture_min= 1.6200
V_fixture_max= 1.9800
|time   V(typ)   V(min)   V(max)
0s        682.5mV    765.7mV    594.8mV
411.8ps   682.5mV    765.7mV    612.9mV
450.3ps   682.7mV    765.7mV    773.7mV
531.8ps   702.8mV    765.7mV    1.424V
620.9ps   1.077V     765.7mV    1.907V
750.4ps   1.622V     766.2mV    1.971V
847ps     1.767V     926.3mV    1.976V
1.11ns    1.796V     1.529V     1.978V
1.546ns   1.799V     1.617V     1.979V
60ns      1.8V       1.62V      1.98V
[Falling Waveform]
R_fixture= 50.0000
V_fixture= 0.0
V_fixture_min= 0.0
V_fixture_max= 0.0
|time   V(typ)   V(min)   V(max)
0s        1.11V      835.6mV    1.383V
466.8ps   1.11V      835.6mV    1.356V
525.7ps   1.111V     835.6mV    1.107V
604.3ps   1.081V     835.6mV    350.3mV
670.8ps   925.8mV    835.6mV    53.53mV
809ps     192.1mV    837.2mV    6.75mV
886.4ps   39.48mV    816.7mV    3.812mV
1.255ns   2.331mV    75.21mV    1.657mV
1.638ns   1.394mV    3.525mV    1.397mV
60ns      474.3nV    5.833uV    249.3nV
[Falling Waveform]
R_fixture= 50.0000
V_fixture= 1.8000
V_fixture_min= 1.6200
V_fixture_max= 1.9800
|time   V(typ)   V(min)   V(max)
0s        1.8V       1.62V      1.98V
496.8ps   1.8V       1.62V      1.971V
569.5ps   1.811V     1.62V      1.728V
681.7ps   1.79V      1.62V      924.5mV
767.7ps   1.61V      1.62V      651.2mV
943.8ps   937.9mV    1.634V     603.9mV
1.045ns   755.5mV    1.622V     599.7mV
1.627ns   685.9mV    873.6mV    596.2mV
2.405ns   683.6mV    771.7mV    595.7mV
60ns      682.5mV    765.7mV    594.8mV
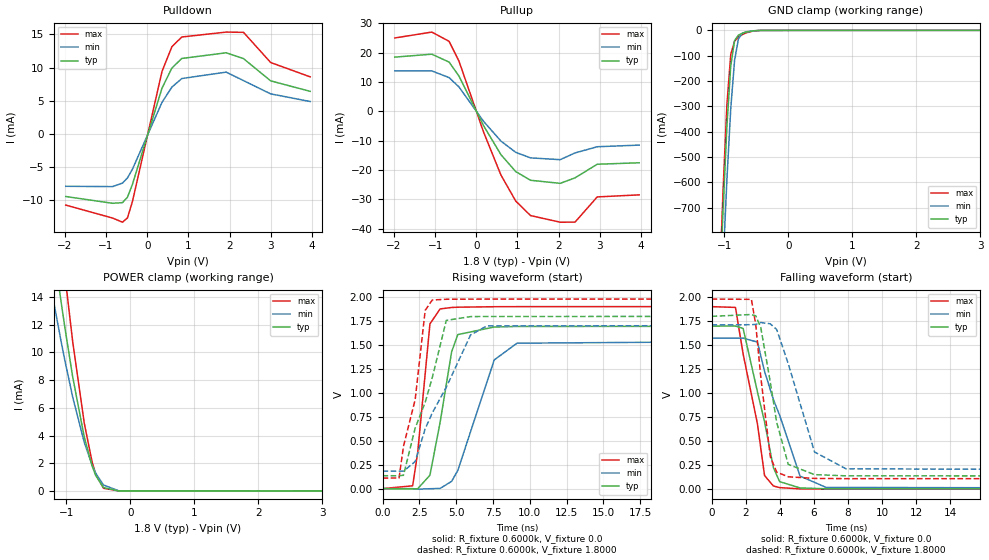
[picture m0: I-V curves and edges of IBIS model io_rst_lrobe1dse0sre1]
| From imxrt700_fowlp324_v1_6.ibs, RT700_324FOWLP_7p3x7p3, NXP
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[Model] io_rst_lrobe1dse0sre1
|   Model io_rst_lrobe1dse0sre1
| This model was characterised for following simulation conditions:
| External (pad) voltage:
|   - Typ: 1.8V,   - Min: 1.71V,   - Max: 1.98V
| Library cells for typ/min/max conditions are connected as defined below:
|  PAD_RST - External Pad
|  ipp_do - Core Input
|  ipp_obe - Output Buffer Enable
|  ASRCN3V3[3] - NC
|  ASRCN3V3[4] - NC
|  ASRCP3V3[4] - NC
|  REFAPBIAS3V3 - gnde
|  REFBAMPL3V3 - vdd1v8
|  REFCAMPH3V3 - vdd1v8
|  REFDNBIAS3V3 - vdd1v8
|  REFH3V3 - REFH3V3
|  REFL3V3 - REFL3V3
|  gnde - gnde
|  ipp_dse - gnde
|  ipp_ina235_3v - NC
|  ipp_ina40_3v - NC
|  ipp_ina_mux - NC
|  ipp_ind - NC
|  ipp_ind_1p8v - NC
|  ipp_ind_3v - NC
|  ipp_sre - vdd
|  vdd - vdd
|  vdd1v8 - vdd1v8
|  vdda - vdde3v3
|  vdde3v3 - vdde3v3
| All other pins connected to ground
Model_type I/O
Polarity   Non-Inverting
Enable   Active-High
Vinl =   0.5400V
Vinh =   1.2600V
Vmeas =  0.9000V
Cref =   15.0000pF
Rref =   0.6000k
Vref =   0.0V
C_comp   3.9805pF   3.7965pF   4.1056pF
|C_comp_pullup   0.3206pF   0.4280pF   0.2789pF
|C_comp_pulldown   2.2502pF   2.3236pF   2.0514pF
[Model Spec]
| variable   typ   min   max
Vinh   1.2600V   NA   NA
Vinl   0.5400V   NA   NA
Vref   0.0V   0.0V   0.0V
Cref   15.0000pF   15.0000pF   15.0000pF
Rref   0.6000k   0.6000k   0.6000k
[Receiver Thresholds]
Vcross_high  =   0.0V
Vcross_low  =   0.0V
Vdiff_ac  =   0.0V
Vdiff_dc  =   0.0V
Tdiffslew_ac  =   0.0S
[Temperature Range]   25.0000   0.1250k   -40.0000
[Voltage Range]   1.8000V   1.7100V   1.9800V
[Pullup Reference]   1.8000V   1.7100V   1.9800V
[Pulldown Reference]   0.0V   0.0V   0.0V
[POWER Clamp Reference]   1.8000V   1.7100V   1.9800V
[GND Clamp Reference]   0.0V   0.0V   0.0V
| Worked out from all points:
|   slope of the pulldown table from 0 to 0.27 V, typ, clamps not added: 50.4 ohm
|   slope of the pullup table from 0 to 0.27 V, typ, clamps not added: 37.3 ohm
|   GND clamp passes 1 mA (typ) near -0.50 V on its own axis
|   POWER clamp passes 1 mA (typ) near -0.53 V on its own axis
|   rising waveform, R_fixture 0.6000k, V_fixture 0.0: 20-80 % time 1.09ns typ, 1.92ns min, 677ps max; typ from 0 V to 1.7 V
|   rising waveform, R_fixture 0.6000k, V_fixture 1.8000: 20-80 % time 1.97ns typ, 2.8ns min, 1.22ns max; typ from 0.135 V to 1.8 V
|   falling waveform, R_fixture 0.6000k, V_fixture 0.0: 20-80 % time 1.3ns typ, 1.7ns min, 1.16ns max; typ from 1.7 V to 0 V
|   falling waveform, R_fixture 0.6000k, V_fixture 1.8000: 20-80 % time 966ps typ, 1.43ns min, 661ps max; typ from 1.8 V to 0.135 V
[Pulldown]
|Voltage   I(typ)   I(min)   I(max)
-1.98V    -9.436mA   -7.895mA   -10.73mA
-840mV    -10.46mA   -7.944mA   -12.69mA
-600mV    -10.36mA   -7.401mA   -13.31mA
-480mV    -9.541mA   -6.639mA   -12.66mA
-360mV    -7.618mA   -5.325mA   -10.21mA
360mV     6.913mA    4.777mA    9.449mA
600mV     9.944mA    7.064mA    13.16mA
840mV     11.38mA    8.356mA    14.62mA
1.92V     12.24mA    9.319mA    15.36mA
2.34V     11.36mA    8.042mA    15.32mA
3V        8.003mA    6.042mA    10.77mA
3.96V     6.425mA    4.891mA    8.61mA
[Pullup]
|Voltage   I(typ)   I(min)   I(max)
-1.98V    18.49mA    13.82mA    25.02mA
-1.08V    19.49mA    13.79mA    27.02mA
-660mV    16.8mA     11.52mA    23.88mA
-420mV    12.05mA    8.333mA    17.13mA
180mV     -4.921mA   -3.425mA   -7.113mA
600mV     -14.73mA   -10.11mA   -21.67mA
960mV     -20.51mA   -13.95mA   -30.55mA
1.32V     -23.46mA   -15.83mA   -35.49mA
2.04V     -24.51mA   -16.44mA   -37.74mA
2.4V      -22.64mA   -14.15mA   -37.73mA
2.94V     -18mA      -12.04mA   -29.13mA
3.96V     -17.5mA    -11.48mA   -28.43mA
[GND_clamp]
|Voltage   I(typ)   I(min)   I(max)
-1.98V    -7.543A    -7.6A      -7.897A
-1.08V    -1.077A    -1.286A    -1.025A
-1.02V    -705.3mA   -921.3mA   -628.8mA
-960mV    -377.1mA   -587.4mA   -291.7mA
-900mV    -139.2mA   -307mA     -94.38mA
-840mV    -40.12mA   -117mA     -42.82mA
-780mV    -18.81mA   -33.95mA   -26.13mA
-720mV    -11.86mA   -11.44mA   -16.78mA
-660mV    -7.061mA   -5.737mA   -9.992mA
-540mV    -1.684mA   -1.901mA   -2.15mA
-420mV    -207.1uA   -403.7uA   -160.6uA
3.96V     0A         0A         0A
[POWER_clamp]
|Voltage   I(typ)   I(min)   I(max)
-1.98V    46.79mA    35.95mA    61.44mA
-1.32V    21.78mA    16.85mA    28.96mA
-1.2V     17.57mA    13.71mA    23.37mA
-1.08V    13.59mA    10.75mA    18.03mA
-1.02V    11.71mA    9.354mA    15.49mA
-900mV    8.21mA     6.76mA     10.75mA
-720mV    3.899mA    3.511mA    4.896mA
-600mV    1.839mA    1.889mA    2.143mA
-540mV    1.103mA    1.267mA    1.197mA
-420mV    244.5uA    429.3uA    190.7uA
-180mV    281nA      5.272uA    27.6nA
3.96V     0A         0A         0A
[Ramp]
| variable   typ   min   max
dV/dt_r  1.0188/1.0920n   0.9441/1.9204n   1.1406/0.6773n
dV/dt_f  0.9990/0.9664n   0.9166/1.4321n   1.1224/0.6610n
R_load = 0.6000k
[Rising Waveform]
R_fixture= 0.6000k
V_fixture= 0.0
V_fixture_min= 0.0
V_fixture_max= 0.0
|time   V(typ)   V(min)   V(max)
0s        119.2nV    3.183uV    128.2nV
2.045ns   -3.089mV   -307.2uV   29.31mV
2.386ns   -1.13mV    -5.793mV   376.4mV
3.218ns   139.7mV    -1.303mV   1.721V
3.909ns   691.8mV    2.05mV     1.877V
4.691ns   1.429V     75.8mV     1.892V
5.112ns   1.609V     190.6mV    1.895V
7.582ns   1.688V     1.344V     1.9V
9.129ns   1.694V     1.519V     1.901V
60ns      1.698V     1.573V     1.901V
[Rising Waveform]
R_fixture= 0.6000k
V_fixture= 1.8000
V_fixture_min= 1.7100
V_fixture_max= 1.9800
|time   V(typ)   V(min)   V(max)
0s        135mV      182.4mV    109.3mV
1.122ns   134.1mV    182.3mV    111.8mV
1.421ns   139.2mV    181.7mV    441.2mV
2.213ns   630.9mV    282.7mV    927.3mV
2.896ns   901.5mV    624.8mV    1.862V
3.373ns   1.157V     789.3mV    1.97V
4.329ns   1.757V     1.059V     1.978V
5.977ns   1.797V     1.605V     1.979V
7.075ns   1.798V     1.699V     1.98V
60ns      1.8V       1.71V      1.98V
[Falling Waveform]
R_fixture= 0.6000k
V_fixture= 0.0
V_fixture_min= 0.0
V_fixture_max= 0.0
|time   V(typ)   V(min)   V(max)
0s        1.698V     1.573V     1.901V
1.401ns   1.699V     1.573V     1.893V
1.85ns    1.674V     1.573V     1.408V
2.689ns   1.014V     1.532V     680mV
3.105ns   702.9mV    1.228V     142mV
3.622ns   225.4mV    934.1mV    33.22mV
3.989ns   78.45mV    770.1mV    16.28mV
5.186ns   12.92mV    136mV      3.019mV
6.719ns   3.942mV    18.2mV     565.2uV
60ns      7.751uV    15.44uV    4.6uV
[Falling Waveform]
R_fixture= 0.6000k
V_fixture= 1.8000
V_fixture_min= 1.7100
V_fixture_max= 1.9800
|time   V(typ)   V(min)   V(max)
0s        1.8V       1.71V      1.98V
2.334ns   1.819V     1.713V     1.977V
2.593ns   1.805V     1.716V     1.711V
2.885ns   1.683V     1.736V     1.168V
3.443ns   1.115V     1.722V     337.7mV
3.816ns   697.5mV    1.663V     178mV
4.494ns   258.5mV    1.307V     129mV
6.036ns   151.2mV    386.9mV    112mV
7.88ns    138.9mV    212.1mV    109.6mV
60ns      135mV      182.4mV    109.3mV
